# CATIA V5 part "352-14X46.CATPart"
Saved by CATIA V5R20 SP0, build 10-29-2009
Part number: 352-14X46
Definition: NONE
Nomenclature: 352-14X46
Source: Unknown
Description: 352-14X46
Bounding box of the stored display mesh (mm): x 0 to 46, y -10 to 10, z -10 to 10
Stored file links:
  C:\Users\Utente\Desktop\IO LAVORO\3D X SITO CF\X SITO\PLASTICA\352\352-14X46.CATPart

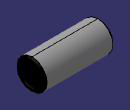
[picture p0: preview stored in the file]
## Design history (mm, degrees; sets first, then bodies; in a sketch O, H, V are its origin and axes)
Body1 "352-14X46" (main body)
  Solid1: solid without history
